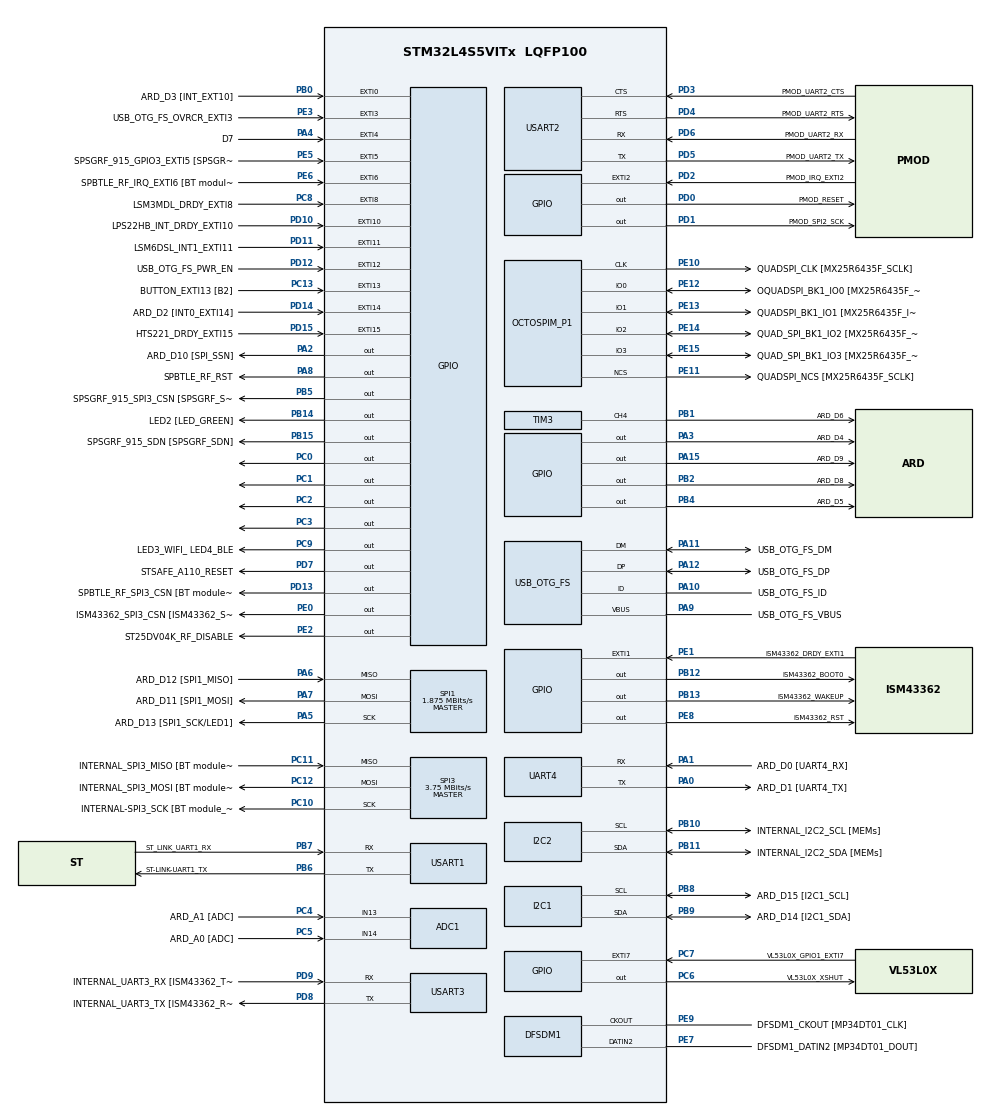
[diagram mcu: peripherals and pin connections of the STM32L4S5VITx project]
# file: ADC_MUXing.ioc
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ADC1.Channel-0\#ChannelRegularConversion=ADC_CHANNEL_13
ADC1.NbrOfConversionFlag=1
ADC1.OffsetNumber-0\#ChannelRegularConversion=ADC_OFFSET_NONE
ADC1.Rank-0\#ChannelRegularConversion=1
ADC1.SamplingTime-0\#ChannelRegularConversion=ADC_SAMPLETIME_2CYCLES_5
ADC1.master=1
I2C1.Timing=0x00101B29
I2C2.Timing=0x00101B29
Mcu.Family=STM32L4
Mcu.Name=STM32L4S5VITx
Mcu.Package=LQFP100
NVIC.EXTI15_10_IRQn=true\:0\:0\:false\:false\:true\:true\:true\:true
NVIC.EXTI4_IRQn=true\:0\:0\:false\:false\:true\:true\:true\:true
NVIC.EXTI9_5_IRQn=true\:0\:0\:false\:false\:true\:true\:true\:true
NVIC.PriorityGroup=NVIC_PRIORITYGROUP_4
NVIC.SPI1_IRQn=true\:0\:0\:false\:false\:true\:true\:true\:true
OCTOSPI1.MemoryType=HAL_OSPI_MEMTYPE_MACRONIX
PA0.GPIO_Label=ARD_D1 [UART4_TX]
PA0.GPIO_ModeDefaultPP=GPIO_MODE_AF_PP
PA0.GPIO_PuPd=GPIO_NOPULL
PA0.GPIO_Speed=GPIO_SPEED_FREQ_VERY_HIGH
PA0.Mode=Asynchronous
PA0.Signal=UART4_TX
PA1.GPIO_Label=ARD_D0 [UART4_RX]
PA1.GPIO_ModeDefaultPP=GPIO_MODE_AF_PP
PA1.GPIO_PuPd=GPIO_NOPULL
PA1.GPIO_Speed=GPIO_SPEED_FREQ_VERY_HIGH
PA1.Mode=Asynchronous
PA1.Signal=UART4_RX
PA10.GPIO_Label=USB_OTG_FS_ID
PA10.Mode=OTG/Dual_Role_Device
PA10.Signal=USB_OTG_FS_ID
PA11.GPIO_Label=USB_OTG_FS_DM
PA11.Mode=OTG/Dual_Role_Device
PA11.Signal=USB_OTG_FS_DM
PA12.GPIO_Label=USB_OTG_FS_DP
PA12.Mode=OTG/Dual_Role_Device
PA12.Signal=USB_OTG_FS_DP
PA13\ (JTMS/SWDIO).GPIO_Label=SYS_JTMS_SWDIO
PA13\ (JTMS/SWDIO).Mode=Serial_Wire
PA13\ (JTMS/SWDIO).Signal=SYS_JTMS-SWDIO
PA14\ (JTCK/SWCLK).GPIO_Label=SYS_JTCK_SWCLK
PA14\ (JTCK/SWCLK).Mode=Serial_Wire
PA14\ (JTCK/SWCLK).Signal=SYS_JTCK-SWCLK
PA15\ (JTDI).GPIO_Label=ARD_D9
PA15\ (JTDI).GPIO_ModeDefaultOutputPP=GPIO_MODE_OUTPUT_PP
PA15\ (JTDI).GPIO_PuPd=GPIO_NOPULL
PA15\ (JTDI).GPIO_Speed=GPIO_SPEED_FREQ_LOW
PA15\ (JTDI).PinState=GPIO_PIN_RESET
PA15\ (JTDI).Signal=GPIO_Output
PA2.GPIO_Label=ARD_D10 [SPI_SSN]
PA2.GPIO_ModeDefaultOutputPP=GPIO_MODE_OUTPUT_PP
PA2.GPIO_PuPd=GPIO_NOPULL
PA2.GPIO_Speed=GPIO_SPEED_FREQ_LOW
PA2.PinState=GPIO_PIN_RESET
PA2.Signal=GPIO_Output
PA3.GPIO_Label=ARD_D4
PA3.Signal=GPIO_Output
PA4.GPIO_Label=D7
PA4.GPIO_ModeDefaultEXTI=GPIO_MODE_IT_FALLING
PA4.Signal=GPXTI4
PA5.GPIO_Label=ARD_D13 [SPI1_SCK/LED1]
PA5.GPIO_Mode=GPIO_MODE_AF_PP
PA5.GPIO_PuPd=GPIO_NOPULL
PA5.GPIO_Speed=GPIO_SPEED_FREQ_VERY_HIGH
PA5.Mode=Full_Duplex_Master
PA5.Signal=SPI1_SCK
PA6.GPIO_Label=ARD_D12 [SPI1_MISO]
PA6.GPIO_Mode=GPIO_MODE_AF_PP
PA6.GPIO_PuPd=GPIO_NOPULL
PA6.GPIO_Speed=GPIO_SPEED_FREQ_VERY_HIGH
PA6.Mode=Full_Duplex_Master
PA6.Signal=SPI1_MISO
PA7.GPIO_Label=ARD_D11 [SPI1_MOSI]
PA7.GPIO_Mode=GPIO_MODE_AF_PP
PA7.GPIO_PuPd=GPIO_NOPULL
PA7.GPIO_Speed=GPIO_SPEED_FREQ_VERY_HIGH
PA7.Mode=Full_Duplex_Master
PA7.Signal=SPI1_MOSI
PA8.GPIO_Label=SPBTLE_RF_RST
PA8.GPIO_ModeDefaultOutputPP=GPIO_MODE_OUTPUT_PP
PA8.GPIO_PuPd=GPIO_NOPULL
PA8.GPIO_Speed=GPIO_SPEED_FREQ_LOW
PA8.PinState=GPIO_PIN_RESET
PA8.Signal=GPIO_Output
PA9.GPIO_Label=USB_OTG_FS_VBUS
PA9.GPIO_Mode=GPIO_MODE_INPUT
PA9.GPIO_PuPd=GPIO_NOPULL
PA9.Mode=Activate_VBUS
PA9.Signal=USB_OTG_FS_VBUS
PB0.GPIO_Label=ARD_D3 [INT_EXT10]
PB0.GPIO_ModeDefaultEXTI=GPIO_MODE_IT_RISING
PB0.GPIO_PuPd=GPIO_NOPULL
PB0.Signal=GPXTI0
PB1.GPIO_Label=ARD_D6
PB1.GPIO_Speed=GPIO_SPEED_FREQ_LOW
PB1.Signal=S_TIM3_CH4
PB10.GPIO_Label=INTERNAL_I2C2_SCL [MEMs]
PB10.GPIO_Mode=GPIO_MODE_AF_OD
PB10.GPIO_Pu=GPIO_PULLUP
PB10.GPIO_Speed=GPIO_SPEED_FREQ_VERY_HIGH
PB10.Mode=I2C
PB10.Signal=I2C2_SCL
PB11.GPIO_Label=INTERNAL_I2C2_SDA [MEMs]
PB11.GPIO_Mode=GPIO_MODE_AF_OD
PB11.GPIO_Pu=GPIO_PULLUP
PB11.GPIO_Speed=GPIO_SPEED_FREQ_VERY_HIGH
PB11.Mode=I2C
PB11.Signal=I2C2_SDA
PB12.GPIO_Label=ISM43362_BOOT0
PB12.GPIO_ModeDefaultOutputPP=GPIO_MODE_OUTPUT_PP
PB12.GPIO_PuPd=GPIO_NOPULL
PB12.GPIO_Speed=GPIO_SPEED_FREQ_LOW
PB12.PinState=GPIO_PIN_RESET
PB12.Signal=GPIO_Output
PB13.GPIO_Label=ISM43362_WAKEUP
PB13.GPIO_ModeDefaultOutputPP=GPIO_MODE_OUTPUT_PP
PB13.GPIO_PuPd=GPIO_NOPULL
PB13.GPIO_Speed=GPIO_SPEED_FREQ_LOW
PB13.PinState=GPIO_PIN_RESET
PB13.Signal=GPIO_Output
PB14.GPIO_Label=LED2 [LED_GREEN]
PB14.GPIO_ModeDefaultOutputPP=GPIO_MODE_OUTPUT_PP
PB14.GPIO_PuPd=GPIO_NOPULL
PB14.GPIO_Speed=GPIO_SPEED_FREQ_LOW
PB14.PinState=GPIO_PIN_RESET
PB14.Signal=GPIO_Output
PB15.GPIO_Label=SPSGRF_915_SDN [SPSGRF_SDN]
PB15.Signal=GPIO_Output
PB2.GPIO_Label=ARD_D8
PB2.GPIO_ModeDefaultOutputPP=GPIO_MODE_OUTPUT_PP
PB2.GPIO_PuPd=GPIO_NOPULL
PB2.GPIO_Speed=GPIO_SPEED_FREQ_LOW
PB2.PinState=GPIO_PIN_RESET
PB2.Signal=GPIO_Output
PB3\ (JTDO/TRACESWO).GPIO_Label=SYS_JTD0_SWO
PB3\ (JTDO/TRACESWO).Signal=SYS_JTDO-SWO
PB4\ (NJTRST).GPIO_Label=ARD_D5
PB4\ (NJTRST).GPIO_ModeDefaultOutputPP=GPIO_MODE_OUTPUT_PP
PB4\ (NJTRST).GPIO_PuPd=GPIO_NOPULL
PB4\ (NJTRST).GPIO_Speed=GPIO_SPEED_FREQ_LOW
PB4\ (NJTRST).PinState=GPIO_PIN_RESET
PB4\ (NJTRST).Signal=GPIO_Output
PB5.GPIO_Label=SPSGRF_915_SPI3_CSN [SPSGRF_SPI_CS]
PB5.Signal=GPIO_Output
PB6.GPIO_FM6=__NULL
PB6.GPIO_Label=ST-LINK-UART1_TX
PB6.GPIO_ModeDefaultPP=GPIO_MODE_AF_PP
PB6.GPIO_PuPd=GPIO_NOPULL
PB6.GPIO_Speed=GPIO_SPEED_FREQ_VERY_HIGH
PB6.Mode=Asynchronous
PB6.Signal=USART1_TX
PB7.GPIO_FM7=__NULL
PB7.GPIO_Label=ST_LINK_UART1_RX
PB7.GPIO_ModeDefaultPP=GPIO_MODE_AF_PP
PB7.GPIO_PuPd=GPIO_NOPULL
PB7.GPIO_Speed=GPIO_SPEED_FREQ_VERY_HIGH
PB7.Mode=Asynchronous
PB7.Signal=USART1_RX
PB8.GPIO_FM8=__NULL
PB8.GPIO_Label=ARD_D15 [I2C1_SCL]
PB8.GPIO_Mode=GPIO_MODE_AF_OD
PB8.GPIO_Pu=GPIO_PULLUP
PB8.GPIO_Speed=GPIO_SPEED_FREQ_VERY_HIGH
PB8.Mode=I2C
PB8.Signal=I2C1_SCL
PB9.GPIO_FM9=__NULL
PB9.GPIO_Label=ARD_D14 [I2C1_SDA]
PB9.GPIO_Mode=GPIO_MODE_AF_OD
PB9.GPIO_Pu=GPIO_PULLUP
PB9.GPIO_Speed=GPIO_SPEED_FREQ_VERY_HIGH
PB9.Mode=I2C
PB9.Signal=I2C1_SDA
PC0.GPIO_Speed=GPIO_SPEED_FREQ_VERY_HIGH
PC0.PinState=GPIO_PIN_RESET
PC0.Signal=GPIO_Output
PC1.GPIO_Speed=GPIO_SPEED_FREQ_VERY_HIGH
PC1.PinState=GPIO_PIN_RESET
PC1.Signal=GPIO_Output
PC10.GPIO_Label=INTERNAL-SPI3_SCK [BT module_SPI_MOSI] [ISM43362_MOSI]
PC10.GPIO_Mode=GPIO_MODE_AF_PP
PC10.GPIO_PuPd=GPIO_NOPULL
PC10.GPIO_Speed=GPIO_SPEED_FREQ_VERY_HIGH
PC10.Mode=Full_Duplex_Master
PC10.Signal=SPI3_SCK
PC11.GPIO_Label=INTERNAL_SPI3_MISO [BT module_SPI_MOSI] [ISM43362_MOSI]
PC11.GPIO_Mode=GPIO_MODE_AF_PP
PC11.GPIO_PuPd=GPIO_NOPULL
PC11.GPIO_Speed=GPIO_SPEED_FREQ_VERY_HIGH
PC11.Mode=Full_Duplex_Master
PC11.Signal=SPI3_MISO
PC12.GPIO_Label=INTERNAL_SPI3_MOSI [BT module_SPI_MOSI] [ISM43362_MOSI]
PC12.GPIO_Mode=GPIO_MODE_AF_PP
PC12.GPIO_PuPd=GPIO_NOPULL
PC12.GPIO_Speed=GPIO_SPEED_FREQ_VERY_HIGH
PC12.Mode=Full_Duplex_Master
PC12.Signal=SPI3_MOSI
PC13.GPIO_Label=BUTTON_EXTI13 [B2]
PC13.GPIO_ModeDefaultEXTI=GPIO_MODE_IT_RISING
PC13.GPIO_PuPd=GPIO_NOPULL
PC13.Signal=GPXTI13
PC14-OSC32_IN\ (PC14).Mode=LSE-External-Oscillator
PC14-OSC32_IN\ (PC14).Signal=RCC_OSC32_IN
PC15-OSC32_OUT\ (PC15).Mode=LSE-External-Oscillator
PC15-OSC32_OUT\ (PC15).Signal=RCC_OSC32_OUT
PC2.GPIO_Speed=GPIO_SPEED_FREQ_VERY_HIGH
PC2.Signal=GPIO_Output
PC3.GPIO_Speed=GPIO_SPEED_FREQ_VERY_HIGH
PC3.Signal=GPIO_Output
PC4.GPIO_Label=ARD_A1 [ADC]
PC4.GPIO_Mode=GPIO_MODE_ANALOG_ADC_CONTROL
PC4.GPIO_PuPd=GPIO_NOPULL
PC4.Signal=ADCx_IN13
PC5.GPIO_Label=ARD_A0 [ADC]
PC5.GPIO_Mode=GPIO_MODE_ANALOG_ADC_CONTROL
PC5.GPIO_PuPd=GPIO_NOPULL
PC5.Signal=ADCx_IN14
PC6.GPIO_Label=VL53L0X_XSHUT
PC6.GPIO_ModeDefaultOutputPP=GPIO_MODE_OUTPUT_PP
PC6.GPIO_PuPd=GPIO_NOPULL
PC6.GPIO_Speed=GPIO_SPEED_FREQ_LOW
PC6.PinState=GPIO_PIN_RESET
PC6.Signal=GPIO_Output
PC7.GPIO_Label=VL53L0X_GPIO1_EXTI7
PC7.GPIO_ModeDefaultEXTI=GPIO_MODE_IT_RISING
PC7.GPIO_PuPd=GPIO_NOPULL
PC7.Signal=GPXTI7
PC8.GPIO_Label=LSM3MDL_DRDY_EXTI8
PC8.GPIO_ModeDefaultEXTI=GPIO_MODE_IT_RISING
PC8.GPIO_PuPd=GPIO_NOPULL
PC8.Signal=GPXTI8
PC9.GPIO_Label=LED3_WIFI_ LED4_BLE
PC9.GPIO_ModeDefaultOutputPP=GPIO_MODE_OUTPUT_PP
PC9.GPIO_PuPd=GPIO_NOPULL
PC9.GPIO_Speed=GPIO_SPEED_FREQ_LOW
PC9.PinState=GPIO_PIN_RESET
PC9.Signal=GPIO_Output
PD0.GPIO_Label=PMOD_RESET
PD0.GPIO_ModeDefaultOutputPP=GPIO_MODE_OUTPUT_PP
PD0.GPIO_PuPd=GPIO_NOPULL
PD0.GPIO_Speed=GPIO_SPEED_FREQ_LOW
PD0.PinState=GPIO_PIN_RESET
PD0.Signal=GPIO_Output
PD1.GPIO_Label=PMOD_SPI2_SCK
PD1.Signal=GPIO_Output
PD10.GPIO_Label=LPS22HB_INT_DRDY_EXTI10
PD10.GPIO_ModeDefaultEXTI=GPIO_MODE_IT_RISING
PD10.GPIO_PuPd=GPIO_NOPULL
PD10.Signal=GPXTI10
PD11.GPIO_Label=LSM6DSL_INT1_EXTI11
PD11.GPIO_ModeDefaultEXTI=GPIO_MODE_IT_RISING
PD11.GPIO_PuPd=GPIO_NOPULL
PD11.Signal=GPXTI11
PD12.GPIO_Label=USB_OTG_FS_PWR_EN
PD12.GPIO_ModeDefaultEXTI=GPIO_MODE_IT_RISING
PD12.GPIO_PuPd=GPIO_NOPULL
PD12.Signal=GPXTI12
PD13.GPIO_Label=SPBTLE_RF_SPI3_CSN [BT module_SPI_CS]
PD13.GPIO_ModeDefaultOutputPP=GPIO_MODE_OUTPUT_PP
PD13.GPIO_PuPd=GPIO_NOPULL
PD13.GPIO_Speed=GPIO_SPEED_FREQ_LOW
PD13.PinState=GPIO_PIN_RESET
PD13.Signal=GPIO_Output
PD14.GPIO_Label=ARD_D2 [INT0_EXTI14]
PD14.GPIO_ModeDefaultEXTI=GPIO_MODE_IT_RISING
PD14.GPIO_PuPd=GPIO_NOPULL
PD14.Signal=GPXTI14
PD15.GPIO_Label=HTS221_DRDY_EXTI15
PD15.GPIO_ModeDefaultEXTI=GPIO_MODE_IT_RISING
PD15.GPIO_PuPd=GPIO_NOPULL
PD15.Signal=GPXTI15
PD2.GPIO_Label=PMOD_IRQ_EXTI2
PD2.GPIO_ModeDefaultEXTI=GPIO_MODE_IT_RISING
PD2.GPIO_PuPd=GPIO_NOPULL
PD2.Signal=GPXTI2
PD3.GPIO_Label=PMOD_UART2_CTS
PD3.GPIO_Mode=GPIO_MODE_AF_PP
PD3.GPIO_PuPd=GPIO_NOPULL
PD3.GPIO_Speed=GPIO_SPEED_FREQ_VERY_HIGH
PD3.Mode=CTS_RTS
PD3.Signal=USART2_CTS
PD4.GPIO_Label=PMOD_UART2_RTS
PD4.GPIO_Mode=GPIO_MODE_AF_PP
PD4.GPIO_PuPd=GPIO_NOPULL
PD4.GPIO_Speed=GPIO_SPEED_FREQ_VERY_HIGH
PD4.Mode=CTS_RTS
PD4.Signal=USART2_RTS
PD5.GPIO_Label=PMOD_UART2_TX
PD5.GPIO_ModeDefaultPP=GPIO_MODE_AF_PP
PD5.GPIO_PuPd=GPIO_NOPULL
PD5.GPIO_Speed=GPIO_SPEED_FREQ_VERY_HIGH
PD5.Mode=Asynchronous
PD5.Signal=USART2_TX
PD6.GPIO_Label=PMOD_UART2_RX
PD6.GPIO_ModeDefaultPP=GPIO_MODE_AF_PP
PD6.GPIO_PuPd=GPIO_NOPULL
PD6.GPIO_Speed=GPIO_SPEED_FREQ_VERY_HIGH
PD6.Mode=Asynchronous
PD6.Signal=USART2_RX
PD7.GPIO_Label=STSAFE_A110_RESET
PD7.GPIO_ModeDefaultOutputPP=GPIO_MODE_OUTPUT_PP
PD7.GPIO_PuPd=GPIO_NOPULL
PD7.GPIO_Speed=GPIO_SPEED_FREQ_LOW
PD7.PinState=GPIO_PIN_RESET
PD7.Signal=GPIO_Output
PD8.GPIO_Label=INTERNAL_UART3_TX [ISM43362_RX]
PD8.GPIO_ModeDefaultPP=GPIO_MODE_AF_PP
PD8.GPIO_PuPd=GPIO_NOPULL
PD8.GPIO_Speed=GPIO_SPEED_FREQ_VERY_HIGH
PD8.Mode=Asynchronous
PD8.Signal=USART3_TX
PD9.GPIO_Label=INTERNAL_UART3_RX [ISM43362_TX]
PD9.GPIO_ModeDefaultPP=GPIO_MODE_AF_PP
PD9.GPIO_PuPd=GPIO_NOPULL
PD9.GPIO_Speed=GPIO_SPEED_FREQ_VERY_HIGH
PD9.Mode=Asynchronous
PD9.Signal=USART3_RX
PE0.GPIO_Label=ISM43362_SPI3_CSN [ISM43362_SSN]
PE0.GPIO_ModeDefaultOutputPP=GPIO_MODE_OUTPUT_PP
PE0.GPIO_PuPd=GPIO_NOPULL
PE0.GPIO_Speed=GPIO_SPEED_FREQ_LOW
PE0.PinState=GPIO_PIN_RESET
PE0.Signal=GPIO_Output
PE1.GPIO_Label=ISM43362_DRDY_EXTI1
PE1.GPIO_ModeDefaultEXTI=GPIO_MODE_IT_RISING
PE1.GPIO_PuPd=GPIO_NOPULL
PE1.Signal=GPXTI1
PE10.GPIO_Label=QUADSPI_CLK [MX25R6435F_SCLK]
PE10.GPIO_Mode=GPIO_MODE_AF_PP
PE10.GPIO_PuPd=GPIO_NOPULL
PE10.GPIO_Speed_High_Default=GPIO_SPEED_FREQ_VERY_HIGH
PE10.Mode=O1_P1_CLK
PE10.Signal=OCTOSPIM_P1_CLK
PE11.GPIO_Label=QUADSPI_NCS [MX25R6435F_SCLK]
PE11.GPIO_Mode=GPIO_MODE_AF_PP
PE11.GPIO_PuPd=GPIO_NOPULL
PE11.GPIO_Speed_High_Default=GPIO_SPEED_FREQ_VERY_HIGH
PE11.Mode=OCTOSPI1_Port1_NCS
PE11.Signal=OCTOSPIM_P1_NCS
PE12.GPIO_Label=OQUADSPI_BK1_IO0 [MX25R6435F_IO0]
PE12.GPIO_Mode=GPIO_MODE_AF_PP
PE12.GPIO_PuPd=GPIO_NOPULL
PE12.GPIO_Speed_High_Default=GPIO_SPEED_FREQ_VERY_HIGH
PE12.Mode=OCTOSPI1_IOL_Port1L
PE12.Signal=OCTOSPIM_P1_IO0
PE13.GPIO_Label=QUADSPI_BK1_IO1 [MX25R6435F_IO1]
PE13.GPIO_Mode=GPIO_MODE_AF_PP
PE13.GPIO_PuPd=GPIO_NOPULL
PE13.GPIO_Speed_High_Default=GPIO_SPEED_FREQ_VERY_HIGH
PE13.Mode=OCTOSPI1_IOL_Port1L
PE13.Signal=OCTOSPIM_P1_IO1
PE14.GPIO_Label=QUAD_SPI_BK1_IO2 [MX25R6435F_IO2]
PE14.GPIO_Mode=GPIO_MODE_AF_PP
PE14.GPIO_PuPd=GPIO_NOPULL
PE14.GPIO_Speed_High_Default=GPIO_SPEED_FREQ_VERY_HIGH
PE14.Mode=OCTOSPI1_IOL_Port1L
PE14.Signal=OCTOSPIM_P1_IO2
PE15.GPIO_Label=QUAD_SPI_BK1_IO3 [MX25R6435F_IO3]
PE15.GPIO_Mode=GPIO_MODE_AF_PP
PE15.GPIO_PuPd=GPIO_NOPULL
PE15.GPIO_Speed_High_Default=GPIO_SPEED_FREQ_VERY_HIGH
PE15.Mode=OCTOSPI1_IOL_Port1L
PE15.Signal=OCTOSPIM_P1_IO3
PE2.GPIO_Label=ST25DV04K_RF_DISABLE
PE2.GPIO_ModeDefaultOutputPP=GPIO_MODE_OUTPUT_PP
PE2.GPIO_PuPd=GPIO_NOPULL
PE2.GPIO_Speed=GPIO_SPEED_FREQ_LOW
PE2.PinState=GPIO_PIN_RESET
PE2.Signal=GPIO_Output
PE3.GPIO_Label=USB_OTG_FS_OVRCR_EXTI3
PE3.GPIO_ModeDefaultEXTI=GPIO_MODE_IT_RISING
PE3.GPIO_PuPd=GPIO_NOPULL
PE3.Signal=GPXTI3
PE5.GPIO_Label=SPSGRF_915_GPIO3_EXTI5 [SPSGRF_GPIO_3]
PE5.Signal=GPXTI5
PE6.GPIO_Label=SPBTLE_RF_IRQ_EXTI6 [BT module_SPI_IRQ]
PE6.GPIO_ModeDefaultEXTI=GPIO_MODE_IT_RISING
PE6.GPIO_PuPd=GPIO_NOPULL
PE6.Signal=GPXTI6
PE7.GPIO_Label=DFSDM1_DATIN2 [MP34DT01_DOUT]
PE7.GPIO_Mode=GPIO_MODE_AF_PP
PE7.GPIO_PuPd=GPIO_NOPULL
PE7.GPIO_Speed=GPIO_SPEED_FREQ_LOW
PE7.Signal=S_DATAIN2DFSDM1
PE8.GPIO_Label=ISM43362_RST
PE8.GPIO_ModeDefaultOutputPP=GPIO_MODE_OUTPUT_PP
PE8.GPIO_PuPd=GPIO_NOPULL
PE8.GPIO_Speed=GPIO_SPEED_FREQ_LOW
PE8.PinState=GPIO_PIN_RESET
PE8.Signal=GPIO_Output
PE9.GPIO_Label=DFSDM1_CKOUT [MP34DT01_CLK]
PE9.GPIO_Mode=GPIO_MODE_AF_PP
PE9.GPIO_PuPd=GPIO_NOPULL
PE9.GPIO_Speed=GPIO_SPEED_FREQ_LOW
PE9.Signal=S_CKOUTDFSDM1
PH0-OSC_IN\ (PH0).Mode=HSE-External-Oscillator
PH0-OSC_IN\ (PH0).Signal=RCC_OSC_IN
PH1-OSC_OUT\ (PH1).Mode=HSE-External-Oscillator
PH1-OSC_OUT\ (PH1).Signal=RCC_OSC_OUT
ProjectManager.HeapSize=0x200
ProjectManager.StackSize=0x400
ProjectManager.TargetToolchain=STM32CubeIDE
RCC.ADCFreq_Value=48000000
RCC.AHBFreq_Value=120000000
RCC.APB1CLKDivider=RCC_HCLK_DIV16
RCC.APB1Freq_Value=7500000
RCC.APB1TimFreq_Value=15000000
RCC.APB2CLKDivider=RCC_HCLK_DIV16
RCC.APB2Freq_Value=7500000
RCC.APB2TimFreq_Value=15000000
RCC.CortexFreq_Value=120000000
RCC.HCLKFreq_Value=120000000
RCC.HSE_VALUE=8000000
RCC.HSI48_VALUE=48000000
RCC.HSI_VALUE=16000000
RCC.MSI_VALUE=4000000
RCC.PLLN=60
RCC.PLLSAI1N=24
RCC.SYSCLKFreq_VALUE=120000000
RCC.SYSCLKSource=RCC_SYSCLKSOURCE_PLLCLK
RCC.USBFreq_Value=48000000
RCC.VCOOutputFreq_Value=240000000
SH.ADCx_IN13.0=ADC1_IN13,IN13-Single-Ended
SH.ADCx_IN14.0=ADC1_IN14,IN14-Single-Ended
SH.S_CKOUTDFSDM1.0=DFSDM1_CKOUT,PDM_SPI_input_from_ch2_and_internal_clock
SH.S_DATAIN2DFSDM1.0=DFSDM1_DATIN2,PDM_SPI_input_from_ch2_and_internal_clock
SH.S_TIM3_CH4.0=TIM3_CH4,PWM Generation4 CH4
SPI1.BaudRatePrescaler=SPI_BAUDRATEPRESCALER_4
SPI1.CalculateBaudRate=1.875 MBits/s
SPI1.DataSize=SPI_DATASIZE_8BIT
SPI1.Direction=SPI_DIRECTION_2LINES
SPI1.Mode=SPI_MODE_MASTER
SPI1.VirtualType=VM_MASTER
SPI3.BaudRatePrescaler=SPI_BAUDRATEPRESCALER_2
SPI3.CalculateBaudRate=3.75 MBits/s
SPI3.DataSize=SPI_DATASIZE_4BIT
SPI3.Direction=SPI_DIRECTION_2LINES
SPI3.Mode=SPI_MODE_MASTER
SPI3.VirtualType=VM_MASTER
TIM3.Channel-PWM\ Generation4\ CH4=TIM_CHANNEL_4
TIM3.OCFastMode_PWM-PWM\ Generation4\ CH4=TIM_OCFAST_ENABLE
TIM3.Period=2
TIM3.Pulse-PWM\ Generation4\ CH4=1
USART1.VirtualMode-Asynchronous=VM_ASYNC
USART2.VirtualMode-Asynchronous=VM_ASYNC
USART3.VirtualMode-Asynchronous=VM_ASYNC
VP_OCTOSPI1_VS_quad.Mode=quad_mode
VP_TIM3_VS_ClockSourceINT.Mode=Internal
board=B-L4S5I-IOT01A

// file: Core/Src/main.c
/* USER CODE BEGIN Header */
/**
  ******************************************************************************
  * @file           : main.c
  * @brief          : Main program body
  ******************************************************************************
  * @attention
  *
  * Copyright (c) 2022 STMicroelectronics.
  * All rights reserved.
  *
  * This software is licensed under terms that can be found in the LICENSE file
  * in the root directory of this software component.
  * If no LICENSE file comes with this software, it is provided AS-IS.
  *
  ******************************************************************************
  */
/* USER CODE END Header */
#include "main.h"

ADC_HandleTypeDef hadc1;

DFSDM_Channel_HandleTypeDef hdfsdm1_channel2;

I2C_HandleTypeDef hi2c1;
I2C_HandleTypeDef hi2c2;

OSPI_HandleTypeDef hospi1;

SPI_HandleTypeDef hspi1;
SPI_HandleTypeDef hspi3;

TIM_HandleTypeDef htim3;

UART_HandleTypeDef huart4;
UART_HandleTypeDef huart1;
UART_HandleTypeDef huart2;
UART_HandleTypeDef huart3;

void SystemClock_Config(void);
void PeriphCommonClock_Config(void);
static void MX_GPIO_Init(void);
static void MX_ADC1_Init(void);
static void MX_DFSDM1_Init(void);
static void MX_I2C1_Init(void);
static void MX_I2C2_Init(void);
static void MX_OCTOSPI1_Init(void);
static void MX_SPI1_Init(void);
static void MX_SPI3_Init(void);
static void MX_TIM3_Init(void);
static void MX_UART4_Init(void);
static void MX_USART1_UART_Init(void);
static void MX_USART2_UART_Init(void);
static void MX_USART3_UART_Init(void);
static void MX_USB_OTG_FS_USB_Init(void);

/* USER CODE BEGIN 0 */
int flagone = 1;
int flagtwo = 1;
int pin = 0;
int flipped = 1;
int flagger = 0;
int dataonewritten = 0;
int datatwowritten = 0;
uint8_t RXone_Data[4] = {0,0,0,0};
uint8_t RXtwo_Data[4] = {0,0,0,0};
int milis = 0;
int counter = 0; //sample counter

void setDataReady(){
	if(flipped){
		if(pin){
			HAL_SPI_Receive_IT(&hspi1, RXone_Data, sizeof(RXone_Data));
			flipped = 0;
		}
		else{
			if(flagone){
				milis = HAL_GetTick();
				flagone = 0;
			}
			HAL_SPI_Receive_IT(&hspi1, RXtwo_Data, sizeof(RXtwo_Data));
			flipped = 0;
		}
	}
}

void HAL_SPI_RxCpltCallback(SPI_HandleTypeDef * hspi)
{
    if(pin){
    	if(flagtwo){
    		if(counter>1000){
    		milis = HAL_GetTick() - milis; //get time for 1k samples
    		flagtwo = 0;
    		flagger = 1;
    		}
    		counter +=1;
    	}
    	HAL_GPIO_WritePin(GPIOC, GPIO_PIN_0, GPIO_PIN_RESET);
    	pin = 0;
    	dataonewritten = 1;
    	flipped = 1;
    }
    else{
    	HAL_GPIO_WritePin(GPIOC, GPIO_PIN_0, GPIO_PIN_SET);
    	pin = 1;
    	datatwowritten = 1;
    	flipped = 1;
    }
}
/* USER CODE END 0 */

int main(void)
{

  /* MCU Configuration--------------------------------------------------------*/

  /* Reset of all peripherals, Initializes the Flash interface and the Systick. */
  HAL_Init();

  /* Configure the system clock */
  SystemClock_Config();

/* Configure the peripherals common clocks */
  PeriphCommonClock_Config();

  /* Initialize all configured peripherals */
  MX_GPIO_Init();
  MX_ADC1_Init();
  MX_DFSDM1_Init();
  MX_I2C1_Init();
  MX_I2C2_Init();
  MX_OCTOSPI1_Init();
  MX_SPI1_Init();
  MX_SPI3_Init();
  MX_TIM3_Init();
  MX_UART4_Init();
  MX_USART1_UART_Init();
  MX_USART2_UART_Init();
  MX_USART3_UART_Init();
  MX_USB_OTG_FS_USB_Init();
  /* USER CODE BEGIN 2 */
  uint8_t RXone_Data_local[1024] = {0};
  int pointerone = 0;
  uint8_t RXtwo_Data_local[1024] = {0};
  int pointertwo = 0;

  //int xd = 0;
  HAL_TIM_Base_Start(&htim3);
  HAL_TIM_PWM_Start(&htim3, TIM_CHANNEL_4);
  HAL_GPIO_WritePin(GPIOC, GPIO_PIN_0, GPIO_PIN_RESET);
  //int milis = HAL_GetTick();

  int time = 0;
  /* USER CODE END 2 */

  /* Infinite loop */
  /* USER CODE BEGIN WHILE */
 // printf("hello");
  //HAL_SPI_Receive_IT(&hspi1, RX_Data, sizeof(RX_Data));

  while (1)
  {
    /* USER CODE END WHILE */

    /* USER CODE BEGIN 3 */
	 if(dataonewritten&&pointerone<1024){
		 memcpy(RXone_Data_local + pointerone, &RXone_Data, 4);
		 pointerone +=4;
		 dataonewritten = 0;
	 }
	 if(datatwowritten&&pointertwo<1024){
		 memcpy(RXtwo_Data_local + pointertwo, &RXtwo_Data, 4);
		 pointertwo +=4;
		 datatwowritten = 0;
	 }
	 memcpy(RXone_Data_local, &RXone_Data, 4); //just copy the data into scope so it can be viewed in debugger
	 memcpy(RXtwo_Data_local, &RXtwo_Data, 4);
	 if(flagger){
		 //HAL_SPI_Receive(&hspi1, RX_Data, sizeof(RX_Data), 5000);
		 //HAL_Delay(5000);
		 time = milis;
		 flagger = 0;
		// milis = HAL_GetTick();
		 //flagger = 0;
	 }
	 //if(received){
		// xd = 1;
	// }
  }
  /* USER CODE END 3 */
}

void SystemClock_Config(void)
{
  RCC_OscInitTypeDef RCC_OscInitStruct = {0};
  RCC_ClkInitTypeDef RCC_ClkInitStruct = {0};

  /** Configure the main internal regulator output voltage
  */
  if (HAL_PWREx_ControlVoltageScaling(PWR_REGULATOR_VOLTAGE_SCALE1_BOOST) != HAL_OK)
  {
    Error_Handler();
  }

  /** Configure LSE Drive Capability
  */
  HAL_PWR_EnableBkUpAccess();
  __HAL_RCC_LSEDRIVE_CONFIG(RCC_LSEDRIVE_LOW);

  /** Initializes the RCC Oscillators according to the specified parameters
  * in the RCC_OscInitTypeDef structure.
  */
  RCC_OscInitStruct.OscillatorType = RCC_OSCILLATORTYPE_LSE|RCC_OSCILLATORTYPE_MSI;
  RCC_OscInitStruct.LSEState = RCC_LSE_ON;
  RCC_OscInitStruct.MSIState = RCC_MSI_ON;
  RCC_OscInitStruct.MSICalibrationValue = 0;
  RCC_OscInitStruct.MSIClockRange = RCC_MSIRANGE_6;
  RCC_OscInitStruct.PLL.PLLState = RCC_PLL_ON;
  RCC_OscInitStruct.PLL.PLLSource = RCC_PLLSOURCE_MSI;
  RCC_OscInitStruct.PLL.PLLM = 1;
  RCC_OscInitStruct.PLL.PLLN = 60;
  RCC_OscInitStruct.PLL.PLLP = RCC_PLLP_DIV2;
  RCC_OscInitStruct.PLL.PLLQ = RCC_PLLQ_DIV2;
  RCC_OscInitStruct.PLL.PLLR = RCC_PLLR_DIV2;
  if (HAL_RCC_OscConfig(&RCC_OscInitStruct) != HAL_OK)
  {
    Error_Handler();
  }

  /** Initializes the CPU, AHB and APB buses clocks
  */
  RCC_ClkInitStruct.ClockType = RCC_CLOCKTYPE_HCLK|RCC_CLOCKTYPE_SYSCLK
                              |RCC_CLOCKTYPE_PCLK1|RCC_CLOCKTYPE_PCLK2;
  RCC_ClkInitStruct.SYSCLKSource = RCC_SYSCLKSOURCE_PLLCLK;
  RCC_ClkInitStruct.AHBCLKDivider = RCC_SYSCLK_DIV1;
  RCC_ClkInitStruct.APB1CLKDivider = RCC_HCLK_DIV4;
  RCC_ClkInitStruct.APB2CLKDivider = RCC_HCLK_DIV8;

  if (HAL_RCC_ClockConfig(&RCC_ClkInitStruct, FLASH_LATENCY_5) != HAL_OK)
  {
    Error_Handler();
  }

  /** Enable MSI Auto calibration
  */
  HAL_RCCEx_EnableMSIPLLMode();
}

void PeriphCommonClock_Config(void)
{
  RCC_PeriphCLKInitTypeDef PeriphClkInit = {0};

  /** Initializes the peripherals clock
  */
  PeriphClkInit.PeriphClockSelection = RCC_PERIPHCLK_USB|RCC_PERIPHCLK_ADC;
  PeriphClkInit.AdcClockSelection = RCC_ADCCLKSOURCE_PLLSAI1;
  PeriphClkInit.UsbClockSelection = RCC_USBCLKSOURCE_PLLSAI1;
  PeriphClkInit.PLLSAI1.PLLSAI1Source = RCC_PLLSOURCE_MSI;
  PeriphClkInit.PLLSAI1.PLLSAI1M = 1;
  PeriphClkInit.PLLSAI1.PLLSAI1N = 24;
  PeriphClkInit.PLLSAI1.PLLSAI1P = RCC_PLLP_DIV2;
  PeriphClkInit.PLLSAI1.PLLSAI1Q = RCC_PLLQ_DIV2;
  PeriphClkInit.PLLSAI1.PLLSAI1R = RCC_PLLR_DIV2;
  PeriphClkInit.PLLSAI1.PLLSAI1ClockOut = RCC_PLLSAI1_48M2CLK|RCC_PLLSAI1_ADC1CLK;
  if (HAL_RCCEx_PeriphCLKConfig(&PeriphClkInit) != HAL_OK)
  {
    Error_Handler();
  }
}

static void MX_ADC1_Init(void)
{

  ADC_ChannelConfTypeDef sConfig = {0};

  /** Common config
  */
  hadc1.Instance = ADC1;
  hadc1.Init.ClockPrescaler = ADC_CLOCK_ASYNC_DIV1;
  hadc1.Init.Resolution = ADC_RESOLUTION_12B;
  hadc1.Init.DataAlign = ADC_DATAALIGN_RIGHT;
  hadc1.Init.ScanConvMode = ADC_SCAN_DISABLE;
  hadc1.Init.EOCSelection = ADC_EOC_SINGLE_CONV;
  hadc1.Init.LowPowerAutoWait = DISABLE;
  hadc1.Init.ContinuousConvMode = DISABLE;
  hadc1.Init.NbrOfConversion = 1;
  hadc1.Init.DiscontinuousConvMode = DISABLE;
  hadc1.Init.ExternalTrigConv = ADC_SOFTWARE_START;
  hadc1.Init.ExternalTrigConvEdge = ADC_EXTERNALTRIGCONVEDGE_NONE;
  hadc1.Init.DMAContinuousRequests = DISABLE;
  hadc1.Init.Overrun = ADC_OVR_DATA_PRESERVED;
  hadc1.Init.OversamplingMode = DISABLE;
  if (HAL_ADC_Init(&hadc1) != HAL_OK)
  {
    Error_Handler();
  }

  /** Configure Regular Channel
  */
  sConfig.Channel = ADC_CHANNEL_13;
  sConfig.Rank = ADC_REGULAR_RANK_1;
  sConfig.SamplingTime = ADC_SAMPLETIME_2CYCLES_5;
  sConfig.SingleDiff = ADC_SINGLE_ENDED;
  sConfig.OffsetNumber = ADC_OFFSET_NONE;
  sConfig.Offset = 0;
  if (HAL_ADC_ConfigChannel(&hadc1, &sConfig) != HAL_OK)
  {
    Error_Handler();
  }

}

static void MX_DFSDM1_Init(void)
{

  hdfsdm1_channel2.Instance = DFSDM1_Channel2;
  hdfsdm1_channel2.Init.OutputClock.Activation = ENABLE;
  hdfsdm1_channel2.Init.OutputClock.Selection = DFSDM_CHANNEL_OUTPUT_CLOCK_SYSTEM;
  hdfsdm1_channel2.Init.OutputClock.Divider = 2;
  hdfsdm1_channel2.Init.Input.Multiplexer = DFSDM_CHANNEL_EXTERNAL_INPUTS;
  hdfsdm1_channel2.Init.Input.DataPacking = DFSDM_CHANNEL_STANDARD_MODE;
  hdfsdm1_channel2.Init.Input.Pins = DFSDM_CHANNEL_SAME_CHANNEL_PINS;
  hdfsdm1_channel2.Init.SerialInterface.Type = DFSDM_CHANNEL_SPI_RISING;
  hdfsdm1_channel2.Init.SerialInterface.SpiClock = DFSDM_CHANNEL_SPI_CLOCK_INTERNAL;
  hdfsdm1_channel2.Init.Awd.FilterOrder = DFSDM_CHANNEL_FASTSINC_ORDER;
  hdfsdm1_channel2.Init.Awd.Oversampling = 1;
  hdfsdm1_channel2.Init.Offset = 0;
  hdfsdm1_channel2.Init.RightBitShift = 0x00;
  if (HAL_DFSDM_ChannelInit(&hdfsdm1_channel2) != HAL_OK)
  {
    Error_Handler();
  }

}

static void MX_I2C1_Init(void)
{

  hi2c1.Instance = I2C1;
  hi2c1.Init.Timing = 0x007074AF;
  hi2c1.Init.OwnAddress1 = 0;
  hi2c1.Init.AddressingMode = I2C_ADDRESSINGMODE_7BIT;
  hi2c1.Init.DualAddressMode = I2C_DUALADDRESS_DISABLE;
  hi2c1.Init.OwnAddress2 = 0;
  hi2c1.Init.OwnAddress2Masks = I2C_OA2_NOMASK;
  hi2c1.Init.GeneralCallMode = I2C_GENERALCALL_DISABLE;
  hi2c1.Init.NoStretchMode = I2C_NOSTRETCH_DISABLE;
  if (HAL_I2C_Init(&hi2c1) != HAL_OK)
  {
    Error_Handler();
  }

  /** Configure Analogue filter
  */
  if (HAL_I2CEx_ConfigAnalogFilter(&hi2c1, I2C_ANALOGFILTER_ENABLE) != HAL_OK)
  {
    Error_Handler();
  }

  /** Configure Digital filter
  */
  if (HAL_I2CEx_ConfigDigitalFilter(&hi2c1, 0) != HAL_OK)
  {
    Error_Handler();
  }

}

static void MX_I2C2_Init(void)
{

  hi2c2.Instance = I2C2;
  hi2c2.Init.Timing = 0x007074AF;
  hi2c2.Init.OwnAddress1 = 0;
  hi2c2.Init.AddressingMode = I2C_ADDRESSINGMODE_7BIT;
  hi2c2.Init.DualAddressMode = I2C_DUALADDRESS_DISABLE;
  hi2c2.Init.OwnAddress2 = 0;
  hi2c2.Init.OwnAddress2Masks = I2C_OA2_NOMASK;
  hi2c2.Init.GeneralCallMode = I2C_GENERALCALL_DISABLE;
  hi2c2.Init.NoStretchMode = I2C_NOSTRETCH_DISABLE;
  if (HAL_I2C_Init(&hi2c2) != HAL_OK)
  {
    Error_Handler();
  }

  /** Configure Analogue filter
  */
  if (HAL_I2CEx_ConfigAnalogFilter(&hi2c2, I2C_ANALOGFILTER_ENABLE) != HAL_OK)
  {
    Error_Handler();
  }

  /** Configure Digital filter
  */
  if (HAL_I2CEx_ConfigDigitalFilter(&hi2c2, 0) != HAL_OK)
  {
    Error_Handler();
  }

}

static void MX_OCTOSPI1_Init(void)
{

  OSPIM_CfgTypeDef OSPIM_Cfg_Struct = {0};

  /* OCTOSPI1 parameter configuration*/
  hospi1.Instance = OCTOSPI1;
  hospi1.Init.FifoThreshold = 1;
  hospi1.Init.DualQuad = HAL_OSPI_DUALQUAD_DISABLE;
  hospi1.Init.MemoryType = HAL_OSPI_MEMTYPE_MACRONIX;
  hospi1.Init.DeviceSize = 32;
  hospi1.Init.ChipSelectHighTime = 1;
  hospi1.Init.FreeRunningClock = HAL_OSPI_FREERUNCLK_DISABLE;
  hospi1.Init.ClockMode = HAL_OSPI_CLOCK_MODE_0;
  hospi1.Init.ClockPrescaler = 1;
  hospi1.Init.SampleShifting = HAL_OSPI_SAMPLE_SHIFTING_NONE;
  hospi1.Init.DelayHoldQuarterCycle = HAL_OSPI_DHQC_DISABLE;
  hospi1.Init.ChipSelectBoundary = 0;
  hospi1.Init.DelayBlockBypass = HAL_OSPI_DELAY_BLOCK_BYPASSED;
  if (HAL_OSPI_Init(&hospi1) != HAL_OK)
  {
    Error_Handler();
  }
  OSPIM_Cfg_Struct.ClkPort = 1;
  OSPIM_Cfg_Struct.NCSPort = 1;
  OSPIM_Cfg_Struct.IOLowPort = HAL_OSPIM_IOPORT_1_LOW;
  if (HAL_OSPIM_Config(&hospi1, &OSPIM_Cfg_Struct, HAL_OSPI_TIMEOUT_DEFAULT_VALUE) != HAL_OK)
  {
    Error_Handler();
  }

}

static void MX_SPI1_Init(void)
{

  /* SPI1 parameter configuration*/
  hspi1.Instance = SPI1;
  hspi1.Init.Mode = SPI_MODE_MASTER;
  hspi1.Init.Direction = SPI_DIRECTION_2LINES;
  hspi1.Init.DataSize = SPI_DATASIZE_8BIT;
  hspi1.Init.CLKPolarity = SPI_POLARITY_LOW;
  hspi1.Init.CLKPhase = SPI_PHASE_1EDGE;
  hspi1.Init.NSS = SPI_NSS_SOFT;
  hspi1.Init.BaudRatePrescaler = SPI_BAUDRATEPRESCALER_4;
  hspi1.Init.FirstBit = SPI_FIRSTBIT_MSB;
  hspi1.Init.TIMode = SPI_TIMODE_DISABLE;
  hspi1.Init.CRCCalculation = SPI_CRCCALCULATION_DISABLE;
  hspi1.Init.CRCPolynomial = 7;
  hspi1.Init.CRCLength = SPI_CRC_LENGTH_DATASIZE;
  hspi1.Init.NSSPMode = SPI_NSS_PULSE_ENABLE;
  if (HAL_SPI_Init(&hspi1) != HAL_OK)
  {
    Error_Handler();
  }

}

static void MX_SPI3_Init(void)
{

  /* SPI3 parameter configuration*/
  hspi3.Instance = SPI3;
  hspi3.Init.Mode = SPI_MODE_MASTER;
  hspi3.Init.Direction = SPI_DIRECTION_2LINES;
  hspi3.Init.DataSize = SPI_DATASIZE_4BIT;
  hspi3.Init.CLKPolarity = SPI_POLARITY_LOW;
  hspi3.Init.CLKPhase = SPI_PHASE_1EDGE;
  hspi3.Init.NSS = SPI_NSS_SOFT;
  hspi3.Init.BaudRatePrescaler = SPI_BAUDRATEPRESCALER_2;
  hspi3.Init.FirstBit = SPI_FIRSTBIT_MSB;
  hspi3.Init.TIMode = SPI_TIMODE_DISABLE;
  hspi3.Init.CRCCalculation = SPI_CRCCALCULATION_DISABLE;
  hspi3.Init.CRCPolynomial = 7;
  hspi3.Init.CRCLength = SPI_CRC_LENGTH_DATASIZE;
  hspi3.Init.NSSPMode = SPI_NSS_PULSE_ENABLE;
  if (HAL_SPI_Init(&hspi3) != HAL_OK)
  {
    Error_Handler();
  }

}

static void MX_TIM3_Init(void)
{

  TIM_ClockConfigTypeDef sClockSourceConfig = {0};
  TIM_MasterConfigTypeDef sMasterConfig = {0};
  TIM_OC_InitTypeDef sConfigOC = {0};

  htim3.Instance = TIM3;
  htim3.Init.Prescaler = 0;
  htim3.Init.CounterMode = TIM_COUNTERMODE_UP;
  htim3.Init.Period = 2;
  htim3.Init.ClockDivision = TIM_CLOCKDIVISION_DIV1;
  htim3.Init.AutoReloadPreload = TIM_AUTORELOAD_PRELOAD_DISABLE;
  if (HAL_TIM_Base_Init(&htim3) != HAL_OK)
  {
    Error_Handler();
  }
  sClockSourceConfig.ClockSource = TIM_CLOCKSOURCE_INTERNAL;
  if (HAL_TIM_ConfigClockSource(&htim3, &sClockSourceConfig) != HAL_OK)
  {
    Error_Handler();
  }
  if (HAL_TIM_PWM_Init(&htim3) != HAL_OK)
  {
    Error_Handler();
  }
  sMasterConfig.MasterOutputTrigger = TIM_TRGO_RESET;
  sMasterConfig.MasterSlaveMode = TIM_MASTERSLAVEMODE_DISABLE;
  if (HAL_TIMEx_MasterConfigSynchronization(&htim3, &sMasterConfig) != HAL_OK)
  {
    Error_Handler();
  }
  sConfigOC.OCMode = TIM_OCMODE_PWM1;
  sConfigOC.Pulse = 1;
  sConfigOC.OCPolarity = TIM_OCPOLARITY_HIGH;
  sConfigOC.OCFastMode = TIM_OCFAST_ENABLE;
  if (HAL_TIM_PWM_ConfigChannel(&htim3, &sConfigOC, TIM_CHANNEL_4) != HAL_OK)
  {
    Error_Handler();
  }
  HAL_TIM_MspPostInit(&htim3);

}

static void MX_UART4_Init(void)
{

  huart4.Instance = UART4;
  huart4.Init.BaudRate = 115200;
  huart4.Init.WordLength = UART_WORDLENGTH_8B;
  huart4.Init.StopBits = UART_STOPBITS_1;
  huart4.Init.Parity = UART_PARITY_NONE;
  huart4.Init.Mode = UART_MODE_TX_RX;
  huart4.Init.HwFlowCtl = UART_HWCONTROL_NONE;
  huart4.Init.OverSampling = UART_OVERSAMPLING_16;
  huart4.Init.OneBitSampling = UART_ONE_BIT_SAMPLE_DISABLE;
  huart4.Init.ClockPrescaler = UART_PRESCALER_DIV1;
  huart4.AdvancedInit.AdvFeatureInit = UART_ADVFEATURE_NO_INIT;
  if (HAL_UART_Init(&huart4) != HAL_OK)
  {
    Error_Handler();
  }
  if (HAL_UARTEx_SetTxFifoThreshold(&huart4, UART_TXFIFO_THRESHOLD_1_8) != HAL_OK)
  {
    Error_Handler();
  }
  if (HAL_UARTEx_SetRxFifoThreshold(&huart4, UART_RXFIFO_THRESHOLD_1_8) != HAL_OK)
  {
    Error_Handler();
  }
  if (HAL_UARTEx_DisableFifoMode(&huart4) != HAL_OK)
  {
    Error_Handler();
  }

}

static void MX_USART1_UART_Init(void)
{

  huart1.Instance = USART1;
  huart1.Init.BaudRate = 115200;
  huart1.Init.WordLength = UART_WORDLENGTH_8B;
  huart1.Init.StopBits = UART_STOPBITS_1;
  huart1.Init.Parity = UART_PARITY_NONE;
  huart1.Init.Mode = UART_MODE_TX_RX;
  huart1.Init.HwFlowCtl = UART_HWCONTROL_NONE;
  huart1.Init.OverSampling = UART_OVERSAMPLING_16;
  huart1.Init.OneBitSampling = UART_ONE_BIT_SAMPLE_DISABLE;
  huart1.Init.ClockPrescaler = UART_PRESCALER_DIV1;
  huart1.AdvancedInit.AdvFeatureInit = UART_ADVFEATURE_NO_INIT;
  if (HAL_UART_Init(&huart1) != HAL_OK)
  {
    Error_Handler();
  }
  if (HAL_UARTEx_SetTxFifoThreshold(&huart1, UART_TXFIFO_THRESHOLD_1_8) != HAL_OK)
  {
    Error_Handler();
  }
  if (HAL_UARTEx_SetRxFifoThreshold(&huart1, UART_RXFIFO_THRESHOLD_1_8) != HAL_OK)
  {
    Error_Handler();
  }
  if (HAL_UARTEx_DisableFifoMode(&huart1) != HAL_OK)
  {
    Error_Handler();
  }

}

static void MX_USART2_UART_Init(void)
{

  huart2.Instance = USART2;
  huart2.Init.BaudRate = 115200;
  huart2.Init.WordLength = UART_WORDLENGTH_8B;
  huart2.Init.StopBits = UART_STOPBITS_1;
  huart2.Init.Parity = UART_PARITY_NONE;
  huart2.Init.Mode = UART_MODE_TX_RX;
  huart2.Init.HwFlowCtl = UART_HWCONTROL_RTS_CTS;
  huart2.Init.OverSampling = UART_OVERSAMPLING_16;
  huart2.Init.OneBitSampling = UART_ONE_BIT_SAMPLE_DISABLE;
  huart2.Init.ClockPrescaler = UART_PRESCALER_DIV1;
  huart2.AdvancedInit.AdvFeatureInit = UART_ADVFEATURE_NO_INIT;
  if (HAL_UART_Init(&huart2) != HAL_OK)
  {
    Error_Handler();
  }
  if (HAL_UARTEx_SetTxFifoThreshold(&huart2, UART_TXFIFO_THRESHOLD_1_8) != HAL_OK)
  {
    Error_Handler();
  }
  if (HAL_UARTEx_SetRxFifoThreshold(&huart2, UART_RXFIFO_THRESHOLD_1_8) != HAL_OK)
  {
    Error_Handler();
  }
  if (HAL_UARTEx_DisableFifoMode(&huart2) != HAL_OK)
  {
    Error_Handler();
  }

}

static void MX_USART3_UART_Init(void)
{

  huart3.Instance = USART3;
  huart3.Init.BaudRate = 115200;
  huart3.Init.WordLength = UART_WORDLENGTH_8B;
  huart3.Init.StopBits = UART_STOPBITS_1;
  huart3.Init.Parity = UART_PARITY_NONE;
  huart3.Init.Mode = UART_MODE_TX_RX;
  huart3.Init.HwFlowCtl = UART_HWCONTROL_NONE;
  huart3.Init.OverSampling = UART_OVERSAMPLING_16;
  huart3.Init.OneBitSampling = UART_ONE_BIT_SAMPLE_DISABLE;
  huart3.Init.ClockPrescaler = UART_PRESCALER_DIV1;
  huart3.AdvancedInit.AdvFeatureInit = UART_ADVFEATURE_NO_INIT;
  if (HAL_UART_Init(&huart3) != HAL_OK)
  {
    Error_Handler();
  }
  if (HAL_UARTEx_SetTxFifoThreshold(&huart3, UART_TXFIFO_THRESHOLD_1_8) != HAL_OK)
  {
    Error_Handler();
  }
  if (HAL_UARTEx_SetRxFifoThreshold(&huart3, UART_RXFIFO_THRESHOLD_1_8) != HAL_OK)
  {
    Error_Handler();
  }
  if (HAL_UARTEx_DisableFifoMode(&huart3) != HAL_OK)
  {
    Error_Handler();
  }

}

static void MX_USB_OTG_FS_USB_Init(void)
{

}

static void MX_GPIO_Init(void)
{
  GPIO_InitTypeDef GPIO_InitStruct = {0};

  /* GPIO Ports Clock Enable */
  __HAL_RCC_GPIOE_CLK_ENABLE();
  __HAL_RCC_GPIOC_CLK_ENABLE();
  __HAL_RCC_GPIOH_CLK_ENABLE();
  __HAL_RCC_GPIOA_CLK_ENABLE();
  __HAL_RCC_GPIOB_CLK_ENABLE();
  __HAL_RCC_GPIOD_CLK_ENABLE();

  /*Configure GPIO pin Output Level */
  HAL_GPIO_WritePin(GPIOE, ST25DV04K_RF_DISABLE_Pin|ISM43362_RST_Pin|ISM43362_SPI3_CSN_Pin, GPIO_PIN_RESET);

  /*Configure GPIO pin Output Level */
  HAL_GPIO_WritePin(GPIOC, GPIO_PIN_0|GPIO_PIN_1|GPIO_PIN_2|GPIO_PIN_3
                          |VL53L0X_XSHUT_Pin|LED3_WIFI__LED4_BLE_Pin, GPIO_PIN_RESET);

  /*Configure GPIO pin Output Level */
  HAL_GPIO_WritePin(GPIOA, ARD_D10_Pin|ARD_D4_Pin|SPBTLE_RF_RST_Pin|ARD_D9_Pin, GPIO_PIN_RESET);

  /*Configure GPIO pin Output Level */
  HAL_GPIO_WritePin(GPIOB, ARD_D8_Pin|ISM43362_BOOT0_Pin|ISM43362_WAKEUP_Pin|LED2_Pin
                          |SPSGRF_915_SDN_Pin|ARD_D5_Pin|SPSGRF_915_SPI3_CSN_Pin, GPIO_PIN_RESET);

  /*Configure GPIO pin Output Level */
  HAL_GPIO_WritePin(GPIOD, SPBTLE_RF_SPI3_CSN_Pin|PMOD_RESET_Pin|PMOD_SPI2_SCK_Pin|STSAFE_A110_RESET_Pin, GPIO_PIN_RESET);

  /*Configure GPIO pins : ST25DV04K_RF_DISABLE_Pin ISM43362_RST_Pin ISM43362_SPI3_CSN_Pin */
  GPIO_InitStruct.Pin = ST25DV04K_RF_DISABLE_Pin|ISM43362_RST_Pin|ISM43362_SPI3_CSN_Pin;
  GPIO_InitStruct.Mode = GPIO_MODE_OUTPUT_PP;
  GPIO_InitStruct.Pull = GPIO_NOPULL;
  GPIO_InitStruct.Speed = GPIO_SPEED_FREQ_LOW;
  HAL_GPIO_Init(GPIOE, &GPIO_InitStruct);

  /*Configure GPIO pins : USB_OTG_FS_OVRCR_EXTI3_Pin SPSGRF_915_GPIO3_EXTI5_Pin SPBTLE_RF_IRQ_EXTI6_Pin ISM43362_DRDY_EXTI1_Pin */
  GPIO_InitStruct.Pin = USB_OTG_FS_OVRCR_EXTI3_Pin|SPSGRF_915_GPIO3_EXTI5_Pin|SPBTLE_RF_IRQ_EXTI6_Pin|ISM43362_DRDY_EXTI1_Pin;
  GPIO_InitStruct.Mode = GPIO_MODE_IT_RISING;
  GPIO_InitStruct.Pull = GPIO_NOPULL;
  HAL_GPIO_Init(GPIOE, &GPIO_InitStruct);

  /*Configure GPIO pins : BUTTON_EXTI13_Pin VL53L0X_GPIO1_EXTI7_Pin LSM3MDL_DRDY_EXTI8_Pin */
  GPIO_InitStruct.Pin = BUTTON_EXTI13_Pin|VL53L0X_GPIO1_EXTI7_Pin|LSM3MDL_DRDY_EXTI8_Pin;
  GPIO_InitStruct.Mode = GPIO_MODE_IT_RISING;
  GPIO_InitStruct.Pull = GPIO_NOPULL;
  HAL_GPIO_Init(GPIOC, &GPIO_InitStruct);

  /*Configure GPIO pins : PC0 PC1 PC2 PC3 */
  GPIO_InitStruct.Pin = GPIO_PIN_0|GPIO_PIN_1|GPIO_PIN_2|GPIO_PIN_3;
  GPIO_InitStruct.Mode = GPIO_MODE_OUTPUT_PP;
  GPIO_InitStruct.Pull = GPIO_NOPULL;
  GPIO_InitStruct.Speed = GPIO_SPEED_FREQ_VERY_HIGH;
  HAL_GPIO_Init(GPIOC, &GPIO_InitStruct);

  /*Configure GPIO pins : ARD_D10_Pin ARD_D4_Pin SPBTLE_RF_RST_Pin ARD_D9_Pin */
  GPIO_InitStruct.Pin = ARD_D10_Pin|ARD_D4_Pin|SPBTLE_RF_RST_Pin|ARD_D9_Pin;
  GPIO_InitStruct.Mode = GPIO_MODE_OUTPUT_PP;
  GPIO_InitStruct.Pull = GPIO_NOPULL;
  GPIO_InitStruct.Speed = GPIO_SPEED_FREQ_LOW;
  HAL_GPIO_Init(GPIOA, &GPIO_InitStruct);

  /*Configure GPIO pin : D7_Pin */
  GPIO_InitStruct.Pin = D7_Pin;
  GPIO_InitStruct.Mode = GPIO_MODE_IT_FALLING;
  GPIO_InitStruct.Pull = GPIO_NOPULL;
  HAL_GPIO_Init(D7_GPIO_Port, &GPIO_InitStruct);

  /*Configure GPIO pin : ARD_D3_Pin */
  GPIO_InitStruct.Pin = ARD_D3_Pin;
  GPIO_InitStruct.Mode = GPIO_MODE_IT_RISING;
  GPIO_InitStruct.Pull = GPIO_NOPULL;
  HAL_GPIO_Init(ARD_D3_GPIO_Port, &GPIO_InitStruct);

  /*Configure GPIO pins : ARD_D8_Pin ISM43362_BOOT0_Pin ISM43362_WAKEUP_Pin LED2_Pin
                           SPSGRF_915_SDN_Pin ARD_D5_Pin SPSGRF_915_SPI3_CSN_Pin */
  GPIO_InitStruct.Pin = ARD_D8_Pin|ISM43362_BOOT0_Pin|ISM43362_WAKEUP_Pin|LED2_Pin
                          |SPSGRF_915_SDN_Pin|ARD_D5_Pin|SPSGRF_915_SPI3_CSN_Pin;
  GPIO_InitStruct.Mode = GPIO_MODE_OUTPUT_PP;
  GPIO_InitStruct.Pull = GPIO_NOPULL;
  GPIO_InitStruct.Speed = GPIO_SPEED_FREQ_LOW;
  HAL_GPIO_Init(GPIOB, &GPIO_InitStruct);

  /*Configure GPIO pins : LPS22HB_INT_DRDY_EXTI10_Pin LSM6DSL_INT1_EXTI11_Pin USB_OTG_FS_PWR_EN_Pin ARD_D2_Pin
                           HTS221_DRDY_EXTI15_Pin PMOD_IRQ_EXTI2_Pin */
  GPIO_InitStruct.Pin = LPS22HB_INT_DRDY_EXTI10_Pin|LSM6DSL_INT1_EXTI11_Pin|USB_OTG_FS_PWR_EN_Pin|ARD_D2_Pin
                          |HTS221_DRDY_EXTI15_Pin|PMOD_IRQ_EXTI2_Pin;
  GPIO_InitStruct.Mode = GPIO_MODE_IT_RISING;
  GPIO_InitStruct.Pull = GPIO_NOPULL;
  HAL_GPIO_Init(GPIOD, &GPIO_InitStruct);

  /*Configure GPIO pins : SPBTLE_RF_SPI3_CSN_Pin PMOD_RESET_Pin PMOD_SPI2_SCK_Pin STSAFE_A110_RESET_Pin */
  GPIO_InitStruct.Pin = SPBTLE_RF_SPI3_CSN_Pin|PMOD_RESET_Pin|PMOD_SPI2_SCK_Pin|STSAFE_A110_RESET_Pin;
  GPIO_InitStruct.Mode = GPIO_MODE_OUTPUT_PP;
  GPIO_InitStruct.Pull = GPIO_NOPULL;
  GPIO_InitStruct.Speed = GPIO_SPEED_FREQ_LOW;
  HAL_GPIO_Init(GPIOD, &GPIO_InitStruct);

  /*Configure GPIO pins : VL53L0X_XSHUT_Pin LED3_WIFI__LED4_BLE_Pin */
  GPIO_InitStruct.Pin = VL53L0X_XSHUT_Pin|LED3_WIFI__LED4_BLE_Pin;
  GPIO_InitStruct.Mode = GPIO_MODE_OUTPUT_PP;
  GPIO_InitStruct.Pull = GPIO_NOPULL;
  GPIO_InitStruct.Speed = GPIO_SPEED_FREQ_LOW;
  HAL_GPIO_Init(GPIOC, &GPIO_InitStruct);

  /*Configure GPIO pin : USB_OTG_FS_VBUS_Pin */
  GPIO_InitStruct.Pin = USB_OTG_FS_VBUS_Pin;
  GPIO_InitStruct.Mode = GPIO_MODE_INPUT;
  GPIO_InitStruct.Pull = GPIO_NOPULL;
  HAL_GPIO_Init(USB_OTG_FS_VBUS_GPIO_Port, &GPIO_InitStruct);

  /*Configure GPIO pins : USB_OTG_FS_ID_Pin USB_OTG_FS_DM_Pin USB_OTG_FS_DP_Pin */
  GPIO_InitStruct.Pin = USB_OTG_FS_ID_Pin|USB_OTG_FS_DM_Pin|USB_OTG_FS_DP_Pin;
  GPIO_InitStruct.Mode = GPIO_MODE_AF_PP;
  GPIO_InitStruct.Pull = GPIO_NOPULL;
  GPIO_InitStruct.Speed = GPIO_SPEED_FREQ_VERY_HIGH;
  GPIO_InitStruct.Alternate = GPIO_AF10_OTG_FS;
  HAL_GPIO_Init(GPIOA, &GPIO_InitStruct);

  /* EXTI interrupt init*/
  HAL_NVIC_SetPriority(EXTI4_IRQn, 0, 0);
  HAL_NVIC_EnableIRQ(EXTI4_IRQn);

  HAL_NVIC_SetPriority(EXTI9_5_IRQn, 0, 0);
  HAL_NVIC_EnableIRQ(EXTI9_5_IRQn);

  HAL_NVIC_SetPriority(EXTI15_10_IRQn, 0, 0);
  HAL_NVIC_EnableIRQ(EXTI15_10_IRQn);

}

void Error_Handler(void)
{
  __disable_irq();
  while (1)
  {
  }
}
